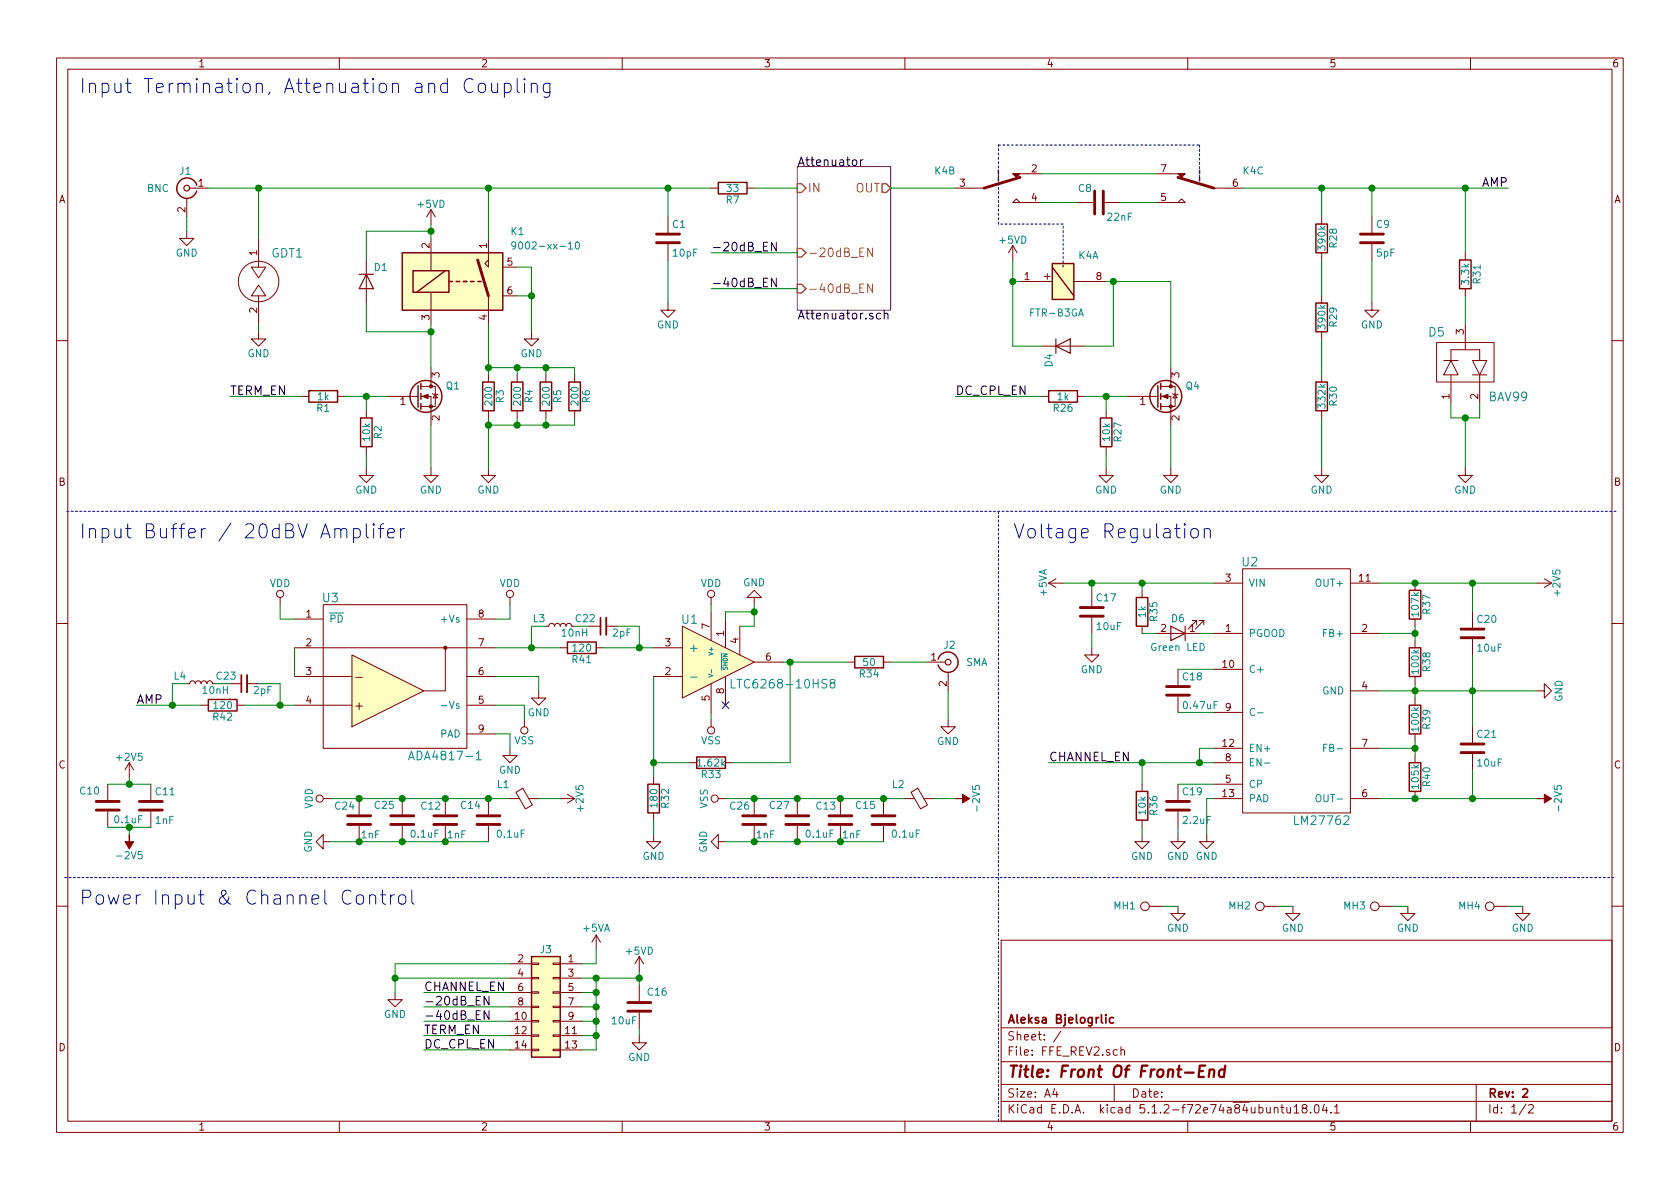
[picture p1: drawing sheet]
<svg xmlns="http://www.w3.org/2000/svg" width="297mm" height="210mm" viewBox="0 0 297 210" stroke-linecap="round" stroke-linejoin="round" font-family="sans-serif">
<defs><g id="words">
<g font-size="3.5" fill="#0000c2">
<text x="14" y="16.5">Input Termination, Attenuation and Coupling</text>
<text x="14" y="95.2">Input Buffer / 20dBV Amplifer</text>
<text x="179.1" y="95.2">Voltage Regulation</text>
<text x="14" y="160">Power Input &amp; Channel Control</text>
</g>
<text font-size="2.8" fill="#840000" x="178" y="190.5">Title: Front Of Front-End</text>
<g font-size="2.1">
<text x="141" y="29.4">Attenuator</text>
<text x="262" y="33">AMP</text>
<text x="125.7" y="44.4">-20dB_EN</text>
<text x="125.7" y="50.8">-40dB_EN</text>
<text x="141" y="56.5">Attenuator.sch</text>
<text x="40.6" y="69.8">TERM_EN</text>
<text x="168.9" y="69.8">DC_CPL_EN</text>
<text x="24.1" y="124.5">AMP</text>
<text x="185.4" y="134.6">CHANNEL_EN</text>
<text x="74.9" y="175.3">CHANNEL_EN</text>
<text x="74.9" y="177.8">-20dB_EN</text>
<text x="74.9" y="182.9">TERM_EN</text>
<text x="74.9" y="180.3">-40dB_EN</text>
<text x="74.9" y="185.4">DC_CPL_EN</text>
</g>
<g font-size="2.1" fill="#848400">
<text x="142.7" y="34">IN</text>
<text x="151.2" y="34">OUT</text>
<text x="142.7" y="45.5">-20dB_EN</text>
<text x="142.7" y="51.8">-40dB_EN</text>
</g>
<g font-size="2.1" fill="#008484">
<text x="48" y="45.5">GDT1</text>
<text x="252.7" y="59.5">D5</text>
<text x="263.3" y="70.9">BAV99</text>
<text x="219.6" y="100.1">U2</text>
<text x="57.1" y="106.5">U3</text>
<text x="120.6" y="110.3">U1</text>
<text x="121.7" y="115.3">+</text>
<text x="130.4" y="121.7">LTC6268-10HS8</text>
<text x="73.2" y="134.4">ADA4817-1</text>
<text x="229.2" y="145.9">LM27762</text>
</g>
<g font-size="2.1" fill="#840000">
<text x="62.9" y="125.5">+</text>
<text x="63.1" y="120.4">-</text>
<text x="178" y="184">Sheet: /</text>
<text x="178" y="181">Aleksa Bjelogrlic</text>
<text x="178" y="186.7">File: FFE_REV2.sch</text>
<text x="178" y="196.9">KiCad E.D.A. kicad 5.1.2-f72e74a84ubuntu18.04.1</text>
<text x="178" y="194.1">Size: A4</text>
<text x="200" y="194.1">Date:</text>
<text x="263" y="194.1">Rev: 2</text>
<text x="263" y="196.9">Id: 1/2</text>
</g>
<g font-size="1.8" fill="#840000">
<text x="35" y="11.9">1</text>
<text x="85" y="11.9">2</text>
<text x="135" y="11.9">3</text>
<text x="185" y="11.9">4</text>
<text x="235" y="11.9">5</text>
<text x="285" y="11.9">6</text>
<text x="10.4" y="35.9">A</text>
<text x="35.1" y="33">1</text>
<text x="169.7" y="33">3</text>
<text x="182.4" y="30.5">2</text>
<text x="182.4" y="35.6">4</text>
<text x="205.3" y="35.6">5</text>
<text x="205.3" y="30.5">7</text>
<text x="218" y="33">6</text>
<text x="285.4" y="35.9">A</text>
<text x="32.8" y="37.6" transform="rotate(-90 32.8 37.6)">2</text>
<text x="45.5" y="45.2" transform="rotate(-90 45.5 45.2)">1</text>
<text x="75.9" y="43.9" transform="rotate(-90 75.9 43.9)">2</text>
<text x="86.1" y="43.9" transform="rotate(-90 86.1 43.9)">1</text>
<text x="89.7" y="47">5</text>
<text x="89.7" y="52.1">6</text>
<text x="181.1" y="49.5">1</text>
<text x="193.8" y="49.5">8</text>
<text x="45.5" y="55.3" transform="rotate(-90 45.5 55.3)">2</text>
<text x="75.9" y="56.6" transform="rotate(-90 75.9 56.6)">3</text>
<text x="86.1" y="56.6" transform="rotate(-90 86.1 56.6)">4</text>
<text x="258.8" y="59.2" transform="rotate(-90 258.8 59.2)">3</text>
<text x="70.8" y="71.6">1</text>
<text x="77.7" y="66.8" transform="rotate(-90 77.7 66.8)">3</text>
<text x="201.6" y="71.6">1</text>
<text x="208.5" y="66.8" transform="rotate(-90 208.5 66.8)">3</text>
<text x="256.3" y="70.6" transform="rotate(-90 256.3 70.6)">1</text>
<text x="261.4" y="70.6" transform="rotate(-90 261.4 70.6)">2</text>
<text x="77.7" y="74.4" transform="rotate(-90 77.7 74.4)">2</text>
<text x="208.5" y="74.4" transform="rotate(-90 208.5 74.4)">2</text>
<text x="10.4" y="85.9">B</text>
<text x="285.4" y="85.9">B</text>
<text x="216.7" y="102.9">3</text>
<text x="240.3" y="102.9">11</text>
<text x="54.1" y="109.2">1</text>
<text x="84.6" y="109.2">8</text>
<text x="125.5" y="111.2" transform="rotate(-90 125.5 111.2)">7</text>
<text x="128" y="112.5" transform="rotate(-90 128 112.5)">1</text>
<text x="130.6" y="113.8" transform="rotate(-90 130.6 113.8)">4</text>
<text x="205.3" y="111.8">2</text>
<text x="210.3" y="111.8">1</text>
<text x="216.7" y="111.8">1</text>
<text x="240.8" y="111.8">2</text>
<text x="54.1" y="114.3">2</text>
<text x="54.1" y="119.4">3</text>
<text x="84.6" y="119.4">6</text>
<text x="84.6" y="114.3">7</text>
<text x="117.6" y="119.4">2</text>
<text x="117.6" y="114.3">3</text>
<text x="135.4" y="116.8">6</text>
<text x="164.6" y="116.8">1</text>
<text x="216.2" y="118.1">10</text>
<text x="54.1" y="124.5">4</text>
<text x="84.6" y="124.5">5</text>
<text x="125.5" y="123.9" transform="rotate(-90 125.5 123.9)">5</text>
<text x="128" y="122.7" transform="rotate(-90 128 122.7)">8</text>
<text x="167.4" y="121.4" transform="rotate(-90 167.4 121.4)">2</text>
<text x="216.7" y="125.7">9</text>
<text x="240.8" y="121.9">4</text>
<text x="84.6" y="129.5">9</text>
<text x="10.4" y="135.9">C</text>
<text x="216.2" y="132.1">12</text>
<text x="216.7" y="134.6">8</text>
<text x="240.8" y="132.1">7</text>
<text x="285.4" y="135.9">C</text>
<text x="216.2" y="141">13</text>
<text x="216.7" y="138.4">5</text>
<text x="240.8" y="141">6</text>
<text x="91.6" y="170.2">2</text>
<text x="91.6" y="172.7">4</text>
<text x="100.5" y="170.2">1</text>
<text x="100.5" y="172.7">3</text>
<text x="91.6" y="175.3">6</text>
<text x="91.6" y="177.8">8</text>
<text x="100.5" y="175.3">5</text>
<text x="100.5" y="177.8">7</text>
<text x="10.4" y="185.9">D</text>
<text x="91.1" y="180.3">10</text>
<text x="91.1" y="182.9">12</text>
<text x="91.1" y="185.4">14</text>
<text x="100" y="182.9">11</text>
<text x="100" y="185.4">13</text>
<text x="100.5" y="180.3">9</text>
<text x="285.4" y="185.9">D</text>
<text x="35" y="199.9">1</text>
<text x="85" y="199.9">2</text>
<text x="135" y="199.9">3</text>
<text x="185" y="199.9">4</text>
<text x="235" y="199.9">5</text>
<text x="285" y="199.9">6</text>
</g>
<g font-size="1.8" fill="#008484">
<text x="26" y="34">BNC</text>
<text x="31.8" y="30.9">J1</text>
<text x="128.4" y="36">R7</text>
<text x="128.6" y="34">33</text>
<text x="165.3" y="30.9">K4B</text>
<text x="190.7" y="34">C8</text>
<text x="219.8" y="30.9">K4C</text>
<text x="74" y="36.7">+5VD</text>
<text x="90.4" y="41.6">K1</text>
<text x="118.9" y="40.3">C1</text>
<text x="195.9" y="39">22nF</text>
<text x="243.4" y="40.3">C9</text>
<text x="31.1" y="45.4">GND</text>
<text x="66.2" y="47.9">D1</text>
<text x="91.9" y="44.1">9002-xx-10</text>
<text x="119.1" y="45.4">10pF</text>
<text x="176.8" y="43.1">+5VD</text>
<text x="190.7" y="45.8">K4A</text>
<text x="234.4" y="44.1" transform="rotate(-90 234.4 44.1)">390k</text>
<text x="236.4" y="43.8" transform="rotate(-90 236.4 43.8)">R28</text>
<text x="243.4" y="45.4">5pF</text>
<text x="259.8" y="50.2" transform="rotate(-90 259.8 50.2)">3.3k</text>
<text x="261.8" y="50.1" transform="rotate(-90 261.8 50.1)">R31</text>
<text x="116.2" y="58.1">GND</text>
<text x="182.3" y="56">FTR-B3GA</text>
<text x="234.4" y="58.1" transform="rotate(-90 234.4 58.1)">390k</text>
<text x="236.4" y="57.7" transform="rotate(-90 236.4 57.7)">R29</text>
<text x="240.6" y="58.1">GND</text>
<text x="43.8" y="63.2">GND</text>
<text x="92" y="63.2">GND</text>
<text x="186.1" y="64.9" transform="rotate(-90 186.1 64.9)">D4</text>
<text x="56.2" y="70.8">1k</text>
<text x="78.9" y="68.9">Q1</text>
<text x="87" y="71.5" transform="rotate(-90 87 71.5)">200</text>
<text x="89.1" y="71.2" transform="rotate(-90 89.1 71.2)">R3</text>
<text x="92.1" y="71.5" transform="rotate(-90 92.1 71.5)">200</text>
<text x="94.2" y="71.2" transform="rotate(-90 94.2 71.2)">R4</text>
<text x="97.2" y="71.5" transform="rotate(-90 97.2 71.5)">200</text>
<text x="99.2" y="71.2" transform="rotate(-90 99.2 71.2)">R5</text>
<text x="102.3" y="71.5" transform="rotate(-90 102.3 71.5)">200</text>
<text x="104.3" y="71.2" transform="rotate(-90 104.3 71.2)">R6</text>
<text x="187" y="70.8">1k</text>
<text x="209.7" y="68.9">Q4</text>
<text x="236.4" y="71.7" transform="rotate(-90 236.4 71.7)">R30</text>
<text x="56" y="72.8">R1</text>
<text x="65.5" y="77.9" transform="rotate(-90 65.5 77.9)">10k</text>
<text x="67.5" y="77.6" transform="rotate(-90 67.5 77.6)">R2</text>
<text x="186.3" y="72.8">R26</text>
<text x="196.3" y="77.9" transform="rotate(-90 196.3 77.9)">10k</text>
<text x="234.4" y="72" transform="rotate(-90 234.4 72)">332k</text>
<text x="198.3" y="78" transform="rotate(-90 198.3 78)">R27</text>
<text x="62.8" y="87.3">GND</text>
<text x="74.2" y="87.3">GND</text>
<text x="84.4" y="87.3">GND</text>
<text x="193.6" y="87.3">GND</text>
<text x="205.1" y="87.3">GND</text>
<text x="231.7" y="87.3">GND</text>
<text x="257.1" y="87.3">GND</text>
<text x="47.7" y="103.8">VDD</text>
<text x="88.3" y="103.8">VDD</text>
<text x="123.9" y="103.8">VDD</text>
<text x="131.4" y="103.7">GND</text>
<text x="185.1" y="105.3" transform="rotate(-90 185.1 105.3)">+5VA</text>
<text x="194" y="106.3">C17</text>
<text x="220.7" y="103.8">VIN</text>
<text x="233" y="103.8">OUT+</text>
<text x="275.9" y="105.2" transform="rotate(-90 275.9 105.2)">+2V5</text>
<text x="58.2" y="110.1">PD</text>
<text x="78.3" y="110.1">+Vs</text>
<text x="94.3" y="110">L3</text>
<text x="101.9" y="110">C22</text>
<text x="108.4" y="112.6">2pF</text>
<text x="194" y="111.4">10uF</text>
<text x="202.6" y="109.2" transform="rotate(-90 202.6 109.2)">1k</text>
<text x="204.6" y="109.8" transform="rotate(-90 204.6 109.8)">R35</text>
<text x="207.2" y="110">D6</text>
<text x="220.7" y="112.6">PGOOD</text>
<text x="234.4" y="112.6">FB+</text>
<text x="250.9" y="108.9" transform="rotate(-90 250.9 108.9)">107k</text>
<text x="252.9" y="108.5" transform="rotate(-90 252.9 108.5)">R37</text>
<text x="261.3" y="110.2">C20</text>
<text x="101.2" y="117.3">R41</text>
<text x="101.4" y="115.2">120</text>
<text x="152" y="119.8">R34</text>
<text x="152.7" y="117.8">50</text>
<text x="166.9" y="114.7">J2</text>
<text x="170.8" y="117.8">SMA</text>
<text x="191.1" y="119">GND</text>
<text x="203.7" y="115.1">Green LED</text>
<text x="220.7" y="119">C+</text>
<text x="250.9" y="119" transform="rotate(-90 250.9 119)">100k</text>
<text x="252.9" y="118.7" transform="rotate(-90 252.9 118.7)">R38</text>
<text x="261.3" y="115.2">10uF</text>
<text x="30.8" y="120.2">L4</text>
<text x="37.9" y="125.4">120</text>
<text x="38.4" y="120.2">C23</text>
<text x="44.9" y="122.7">2pF</text>
<text x="78.8" y="125.3">-Vs</text>
<text x="209.2" y="120.3">C18</text>
<text x="209.4" y="125.4">0.47uF</text>
<text x="233.8" y="122.8">GND</text>
<text x="276.3" y="124.1" transform="rotate(-90 276.3 124.1)">GND</text>
<text x="37.7" y="127.4">R42</text>
<text x="77.8" y="130.4">PAD</text>
<text x="91" y="131.6">VSS</text>
<text x="93.3" y="126.7">GND</text>
<text x="124" y="131.6">VSS</text>
<text x="165.7" y="131.7">GND</text>
<text x="250.9" y="129.2" transform="rotate(-90 250.9 129.2)">100k</text>
<text x="252.9" y="128.8" transform="rotate(-90 252.9 128.8)">R39</text>
<text x="261.3" y="130.5">C21</text>
<text x="20.8" y="134.5">+2V5</text>
<text x="88.2" y="136.8">GND</text>
<text x="123.5" y="135.6">1.62k</text>
<text x="124.1" y="137.6">R33</text>
<text x="220.7" y="133">EN+</text>
<text x="220.7" y="135.5">EN-</text>
<text x="234.8" y="133">FB-</text>
<text x="261.3" y="135.6">10uF</text>
<text x="14.2" y="140.5">C10</text>
<text x="27.6" y="140.6">C11</text>
<text x="55.3" y="143" transform="rotate(-90 55.3 143)">VDD</text>
<text x="59.3" y="143.2">C24</text>
<text x="66.3" y="143">C25</text>
<text x="74.5" y="143.2">C12</text>
<text x="81.6" y="143">C14</text>
<text x="88" y="139.4">L1</text>
<text x="103.2" y="143.3" transform="rotate(-90 103.2 143.3)">+2V5</text>
<text x="116.3" y="142.7" transform="rotate(-90 116.3 142.7)">180</text>
<text x="118.3" y="142.8" transform="rotate(-90 118.3 142.8)">R32</text>
<text x="125.1" y="143" transform="rotate(-90 125.1 143)">VSS</text>
<text x="129.2" y="143.2">C26</text>
<text x="136.2" y="143">C27</text>
<text x="144.4" y="143.2">C13</text>
<text x="151.4" y="143">C15</text>
<text x="157.8" y="139.4">L2</text>
<text x="173.3" y="143.1" transform="rotate(-90 173.3 143.1)">-2V5</text>
<text x="202.6" y="144" transform="rotate(-90 202.6 144)">10k</text>
<text x="209.2" y="140.6">C19</text>
<text x="220.7" y="141.9">PAD</text>
<text x="220.7" y="139.3">CP</text>
<text x="233.4" y="141.9">OUT-</text>
<text x="250.9" y="139.3" transform="rotate(-90 250.9 139.3)">105k</text>
<text x="252.9" y="139" transform="rotate(-90 252.9 139)">R40</text>
<text x="276.1" y="143.1" transform="rotate(-90 276.1 143.1)">-2V5</text>
<text x="20.4" y="145.6">0.1uF</text>
<text x="27.5" y="145.7">1nF</text>
<text x="63.9" y="148.3">1nF</text>
<text x="72.8" y="148.1">0.1uF</text>
<text x="79.2" y="148.3">1nF</text>
<text x="88" y="148.1">0.1uF</text>
<text x="133.8" y="148.3">1nF</text>
<text x="142.6" y="148.1">0.1uF</text>
<text x="149" y="148.3">1nF</text>
<text x="157.9" y="148.1">0.1uF</text>
<text x="204.6" y="144.1" transform="rotate(-90 204.6 144.1)">R36</text>
<text x="209.3" y="145.7">2.2uF</text>
<text x="21" y="151.9">-2V5</text>
<text x="55.2" y="150.8" transform="rotate(-90 55.2 150.8)">GND</text>
<text x="113.6" y="152.1">GND</text>
<text x="125" y="150.8" transform="rotate(-90 125 150.8)">GND</text>
<text x="200" y="152.1">GND</text>
<text x="206.3" y="152.1">GND GND</text>
<text x="197" y="160.8">MH1</text>
<text x="217.3" y="160.8">MH2</text>
<text x="237.6" y="160.8">MH3</text>
<text x="258" y="160.8">MH4</text>
<text x="103.2" y="164.8">+5VA</text>
<text x="206.3" y="164.8">GND</text>
<text x="226.6" y="164.8">GND</text>
<text x="247" y="164.8">GND</text>
<text x="267.3" y="164.8">GND</text>
<text x="95.6" y="168.6">J3</text>
<text x="110.8" y="168.8">+5VD</text>
<text x="114.6" y="176.1">C16</text>
<text x="67.9" y="180">GND</text>
<text x="108.3" y="181.1">10uF</text>
<text x="111.1" y="187.6">GND</text>
</g>
<g font-size="1.8" fill="#008400">
<text x="99.4" y="112.6">10nH</text>
<text x="35.9" y="122.7">10nH</text>
</g>
<g font-size="1.1" fill="#008484">
<text x="126.1" y="115.6" transform="rotate(-90 126.1 115.6)">V+</text>
<text x="128.7" y="118.6" transform="rotate(-90 128.7 118.6)">SHDN</text>
</g>
</g></defs>
<g fill="none" stroke="#840000" stroke-width=".18">
<path d="M10 10.3h277v189.9h-277zM12 12.2h273v186.1h-273zM60 10.3v1.9M110 10.3v1.9M160 10.3v1.9M210 10.3v1.9M260 10.3v1.9M33 35v3.3M33.5 33.3h3.3M76.2 37.1v2.5M76.2 37.1l-.8 1.2M76.2 37.1l.8 1.2"/>
<path d="M118.1 38.3v2.8M125.7 33.3h1.3M132.1 33.3h1.2M168.9 33.3h5.1M179.1 30.7h5M180.3 35.8l-.6-.6-.6 .6h5M190.5 35.8h2.8M195.3 35.8h2.8M204.5 35.8h5l-.6-.6-.6 .6M204.5 30.7h5M214.6 33.3h5.1M233.7 38.3v1.3"/>
<path d="M242.6 38.3v2.8M33 40.9v1.3h1.3l-1.3 1.2-1.3-1.2h1.3M44.4 47.2h2.6l-1.3 1.9zM45.7 50.4l1.3 1.9h-2.6zM45.7 58.7v1.2h1.3l-1.3 1.3-1.3-1.3h1.3M45.7 42.2v5M45.7 52.3v5.1M64.8 46v7.6M76.2 42.2v5.7M76.2 51.7v5.7M86.4 46v1.2l-.7-.6zM86.4 42.2v3.8"/>
<path d="M86.4 52.3v5.1M88.9 47.2h2.5M88.9 52.3h2.5M94 58.7v1.2h1.2l-1.2 1.3-1.3-1.3h1.3M118.1 53.6v1.3h1.3l-1.3 1.2-1.3-1.2h1.3M118.1 43.2v2.8M179.1 43.4l-.8 1.3M179.1 43.4v2.6M179.1 43.4l.7 1.3M180.3 49.8h5.8M184.7 48.9h1M185.2 48.4v1"/>
<path d="M189.9 49.8h5.7M233.7 44.7v1.3M233.7 52.3v1.3M233.7 58.7v1.2M242.6 53.6v1.3h1.2l-1.2 1.2-1.3-1.2h1.3M242.6 43.2v2.8M259.1 44.7v1.3M259.1 51v1.3M259.1 57.4v4.4M10 60.2h2M53.3 70.1h1.3M59.7 70.1h1.3"/>
<path d="M64.8 72.6v1.3M64.8 79v1.3M68.6 70.1h5.3M74.4 70.1h1.8v5.1M74.4 68.3h1.8M76.2 68.3h.8v3.6h-2.6M76.2 65v3.3M76.5 69.6l.1 .1h.7l.2 .1M77 69.7l.3 .7h-.7zM86.4 66.3v1.3M86.4 72.6v1.3M91.4 66.3v1.3"/>
<path d="M91.4 72.6v1.3M96.5 66.3v1.3M96.5 72.6v1.3M101.6 66.3v1.3M101.6 72.6v1.3M184.1 70.1h1.3M184.1 61.2h7.7M190.5 70.1h1.3M195.6 72.6v1.3M195.6 79v1.3M199.4 70.1h5.3M205.2 70.1h1.8v5.1"/>
<path d="M205.2 68.3h1.8M207 68.3h.8v3.6h-2.6M207 65v3.3M207.3 69.6l.1 .1h.8l.1 .1M207.8 69.7l.4 .7h-.8zM233.7 66.3v1.3M233.7 72.6v1.3M254 60.6h10.2v7h-10.2zM255.3 63.7h2.5M256.5 61.8v1.9zM256.5 61.8h5.1zM256.5 63.7l1.3 2.6h-2.5z"/>
<path d="M256.5 66.3v5.1M260.3 63.7h2.6l-1.3 2.6zM260.3 66.3h2.6M261.6 61.8v1.9zM261.6 66.3v5.1M285 60.2h2M64.8 82.8v1.3h1.2l-1.2 1.2-1.3-1.2h1.3M76.2 82.8v1.3h1.3l-1.3 1.2-1.3-1.2h1.3M86.4 82.8v1.3h1.2l-1.2 1.2-1.3-1.2h1.3M195.6 82.8v1.3h1.2l-1.2 1.2-1.3-1.2h1.3M207 82.8v1.3h1.3l-1.3 1.2-1.3-1.2h1.3M233.7 82.8v1.3h1.2l-1.2 1.2-1.3-1.2h1.3"/>
<path d="M259.1 82.8v1.3h1.2l-1.2 1.2-1.3-1.2h1.3M10 110.3h2M49.5 105.7v1.2M52.1 119.6h10.1M52.1 114.5h35.5M52.1 109.5h5M57.1 106.9h25.4v25.4h-25.4zM62.2 115.8l12.7 6.4-12.7 6.3zM78.7 114.5v7.7h-3.8M82.5 119.6h5.1M82.5 109.5h5.1M90.2 105.7v1.2"/>
<path d="M96.5 110.7h.5l.2-.3 .2-.2 .5 .2 .1 .3 .2-.3 .3-.2 .4 .2 .2 .3 .1-.3 .3-.2 .4 .2 .2 .3 .2-.4 .4-.1 .3 .2 .1 .3M99.1 114.5h1.2M104.1 110.7h2.1M105.4 114.5h1.3M107.2 110.7h2M115.6 119.6h5M115.6 114.5h5M120.6 110.7l12.7 6.4-12.7 6.3zM125.7 105.7v1.2M125.7 108.2v5.1M128.3 109.5v5M128.3 119.6v5.1"/>
<path d="M130.8 110.7v5.1M133.3 105.7h1.3l-1.3-1.3-1.2 1.3h1.2v1.2M133.3 117.1h5.1M149.9 117.1h1.2M156.2 117.1h1.3M163.8 117.1h3.3M167.6 118.9v3.3M185.4 103.1h2.6M185.4 103.1l1.3 .8M186.7 102.4l-1.3 .7M193 114.5v1.3h1.3l-1.3 1.3-1.2-1.3h1.2M193 104.4v2.8"/>
<path d="M193 109.2v2.8M201.9 104.4v1.3M201.9 110.7v1.3M204.5 112h7.6M208.3 118.4v2.8M211.6 110.5v-.8h-.8h.8l-1.5 1.5M212.9 110.5v-.8h-.8h.8l-1.6 1.5M214.6 112h5.1M214.6 118.4h5.1M214.6 103.1h5.1M219.7 100.6h19.1v43.2h-19.1zM238.8 112h5"/>
<path d="M238.8 103.1h5M250.2 103.1v1.3M250.2 109.5v1.2M250.2 113.3v1.2M250.2 119.6v1.3M260.3 108.2v2.8M260.3 113v2.8M271.8 103.1h2.5M273 102.4l1.3 .7M274.3 103.1l-1.3 .8M285 110.3h2M19 138.7v2.8"/>
<path d="M22.9 134.9l-.8 1.2M22.9 134.9v2.5M22.9 134.9l.7 1.2M26.7 138.7v2.8M33 120.9h.5l.2-.3 .2-.2 .5 .1 .1 .4 .2-.3 .3-.2 .4 .1 .2 .4 .1-.3 .3-.2 .4 .1 .2 .4 .2-.4 .4-.1 .3 .2 .1 .3M35.6 124.7h1.2M40.6 120.9h2.1M41.9 124.7h1.3M43.7 120.9h2M52.1 124.7h10.1M82.5 124.7h5.1M82.5 129.8h5.1"/>
<path d="M90.2 132.3v1.3h1.2l-1.2 1.3-1.3-1.3h1.3M92.7 127.2v1.3M95.2 122.2v1.2h1.3l-1.3 1.3-1.2-1.3h1.2M115.6 137.4v1.3M121.9 134.9h1.3M125.7 120.9v5.1M125.7 127.2v1.3M128.3 134.9h1.2M167.6 127.2v1.3h1.3l-1.3 1.3-1.2-1.3h1.2M201.9 138.7v1.2M208.3 123.2v2.8M208.3 138.7v2.8"/>
<path d="M214.6 134.9h5.1M214.6 132.3h5.1M214.6 138.7h5.1M214.6 126h5.1M238.8 132.3h5M238.8 122.2h5M250.2 123.4v1.3M250.2 129.8v1.3M250.2 133.6v1.3M250.2 139.9v1.3M260.3 128.5v2.8M260.3 133.3v2.8"/>
<path d="M271.8 122.2h1.2v-1.3l1.3 1.3-1.3 1.2v-1.2M19 143.5v2.8M26.7 143.5v2.8M57.1 148.8v1.3l-1.2-1.3 1.2-1.2v1.2h1.3M57.1 141.2h1.3M63.5 141.2v2.8M63.5 146v2.8M71.1 141.2v2.8M71.1 146v2.8M78.7 141.2v2.8M78.7 146v2.8M86.4 141.2v2.8"/>
<path d="M86.4 146v2.8M90.2 141.2h1.6M91.2 140.1l1.2-.7 1.7 2.9-1.2 .7zM93.5 141.2h1.7M99.1 141.2h2.5M100.3 140.5l1.3 .7M101.6 141.2l-1.3 .8M115.6 147.6v1.2h1.2l-1.2 1.3-1.3-1.3h1.3M115.6 143.8v1.2M127 148.8v1.3l-1.3-1.3 1.3-1.2v1.2h1.3M127 141.2h1.3M133.3 141.2v2.8"/>
<path d="M133.3 146v2.8M141 141.2v2.8M141 146v2.8M148.6 141.2v2.8M148.6 146v2.8M156.2 141.2v2.8M156.2 146v2.8M160 141.2h1.7M161.1 140.1l1.2-.7 1.7 2.9-1.2 .7zM163.3 141.2h1.8M201.9 147.6v1.2h1.3l-1.3 1.3-1.2-1.3h1.2M201.9 145v1.3"/>
<path d="M208.3 147.6v1.2h1.2l-1.2 1.3-1.3-1.3h1.3M208.3 143.5v2.8M213.4 147.6v1.2h1.2l-1.2 1.3-1.3-1.3h1.3M214.6 141.2h5.1M238.8 141.2h5M10 160.2h2M69.8 175.5v1.3h1.3l-1.3 1.2-1.2-1.2h1.2M90.2 170.4h3.8M90.2 173h3.8M90.2 175.5h3.8M90.2 178h3.8M94 177.9h1.2v.3h-1.2z"/>
<path d="M94 175.4h1.2v.2h-1.2zM94 172.8h1.2v.3h-1.2zM94 170.3h1.2v.3h-1.2zM97.8 177.9h1.3v.3h-1.3zM97.8 175.4h1.3v.2h-1.3zM97.8 172.8h1.3v.3h-1.3zM97.8 170.3h1.3v.3h-1.3zM99.1 170.4h3.8M99.1 173h3.8M99.1 175.5h3.8M99.1 178h3.8M105.4 165.3l-.8 1.3"/>
<path d="M105.4 165.3v2.6M105.4 165.3l.8 1.3M113 169.2v2.5M113 174.2v2.8M113 179.1v2.8M113 169.2l-.7 1.2M113 169.2l.8 1.2M177 166.3h108v32h-108zM203.2 160.3h2.5M208.3 160.3v1.2h1.2l-1.2 1.3-1.3-1.3h1.3M223.5 160.3h2.6M228.6 160.3v1.2h1.3l-1.3 1.3-1.3-1.3h1.3"/>
<path d="M243.8 160.3h2.6M248.9 160.3v1.2h1.3l-1.3 1.3-1.3-1.3h1.3M264.2 160.3h2.5M269.2 160.3v1.2h1.3l-1.3 1.3-1.2-1.3h1.2M285 160.2h2M60 198.3v1.9M90.2 180.6h3.8M90.2 183.1h3.8M90.2 185.7h3.8M94 185.5h1.2v.3h-1.2zM94 183h1.2v.3h-1.2zM94 180.5h1.2v.2h-1.2z"/>
<path d="M97.8 185.5h1.3v.3h-1.3zM97.8 183h1.3v.3h-1.3zM97.8 180.5h1.3v.2h-1.3zM99.1 180.6h3.8M99.1 183.1h3.8M99.1 185.7h3.8M110 198.3v1.9M113 183.1v1.3h-1.2l1.2 1.3 1.3-1.3h-1.3M160 198.3v1.9M177 194.8h108M177 191.8h108M177 187.8h108"/>
<path d="M177 181.8h108M186.5 192.5l-.4 1h1M186.8 193v1M187.6 182.3l-1.3 2M197 191.8v3M197.6 185.7l-.5-.1-.3 .3 .1 .6 .2 .1 .5-.1M198.2 185.7l.2-.1 .4 .1v.9M198.2 185.1v1.5M210 198.3v1.9M225.3 196l.1-.1a.37 .37 0 0 1 .6 .1v.8M226.4 195.8h.6M226.7 195.3v1.3l.3 .2"/>
<path d="M227.5 195.8l.1 .9 .3 .1 .3-.1M228.2 195.8v1M228.8 195.8l.4-.5v1.5M228.8 196.8h.9M230.5 196l-.2-.2-.1-.2 .3-.3h.3l.3 .3-.1 .2-.6 .2a.48 .48 0 0 0-.1 .7l.2 .1 .5-.1a.48 .48 0 0 0-.2-.7M231.7 196.7v.1M232.5 195.5l.4-.2a.94 .94 0 0 1 0 1.5l-.5-.3v-.6zM234.2 195.2l-.4 1.1h.9M234.5 195.8v1M235.3 196.7v.1M235.9 195.8l.5-.5v1.5M235.9 196.8h.9"/>
<path d="M260 198.3v1.9M261 191.8v6.5M269.8 195.2l-1.2 2M270.3 195.5l.2-.2h.3l.3 .5-.9 1h.9"/>
<circle cx="45.7" cy="49.8" r="3.6"/>
<circle cx="49.5" cy="105" r=".63"/>
<circle cx="78.7" cy="114.5" r=".18"/>
<circle cx="78.7" cy="114.5" r=".13"/>
<circle cx="78.7" cy="114.5" r=".28"/>
<circle cx="90.2" cy="105" r=".63"/>
<circle cx="125.7" cy="105" r=".63"/>
<circle cx="92.7" cy="129.2" r=".63"/>
<circle cx="125.7" cy="129.2" r=".63"/>
<circle cx="56.5" cy="141.2" r=".63"/>
<circle cx="126.4" cy="141.2" r=".63"/>
<circle cx="202.4" cy="160.3" r=".76"/>
<circle cx="222.8" cy="160.3" r=".76"/>
<circle cx="243.1" cy="160.3" r=".76"/>
<circle cx="263.4" cy="160.3" r=".76"/>
</g>
<path d="M42.7 119.4v3M106.2 109.2v3.1M195.5 179.4v.2M195.5 179.9v1M196.9 180l-.4-.1-.3 .3v.6l.3 .1 .4-.1M269.2 192.7l.3-.2h.3l.3 .5-.9 1h.9" fill="none" stroke="#840000" stroke-width=".3"/>
<path d="M212 189.4h.7M213.1 188.4h-1l-.2 2h1M213.9 189.3a.5 .5 0 0 1 .8 .1l-.1 1M213.9 189.1l-.2 1.3M216.5 189.2a.68 .68 0 0 0-1 .3v.8l.3 .1 .6-.1M216.6 188.4l-.2 2" fill="none" stroke="#840000" stroke-width=".41"/>
<g fill="none" stroke="#840000" stroke-width=".25">
<path d="M34.8 32.8a1.8 1.8 0 0 0-2.7-1.1 1.8 1.8 0 0 0-.1 3 1.8 1.8 0 0 0 2.8-.9M127 32.3h5.1v2h-5.1zM176.5 30.1v.6M176.5 31.4v.6M212.1 30.1v.6M212.1 31.4v.6M232.7 39.6h2v5.1h-2zM71.1 44.7h17.8v10.2h-17.8zM73 47.9h6.4v3.8h-6.4zM78.7 47.9l-5 3.8M79.4 49.8h.6M80.6 49.8h.7"/>
<path d="M81.9 49.8h.6M83.2 49.8h.6M84.5 49.8h.6M186.1 46.6h3.8v6.4h-3.8zM186.1 47.2l3.8 5.1M232.7 53.6h2v5.1h-2zM258.1 46h2v5h-2zM54.6 69.1h5.1v2h-5.1zM63.8 73.9h2v5.1h-2zM73.9 68.2v3.8M74.4 67.8v1M74.4 69.6v1"/>
<path d="M74.4 71.4v1M85.3 67.6h2.1v5h-2.1zM90.4 67.6h2.1v5h-2.1zM95.5 67.6h2v5h-2zM100.6 67.6h2v5h-2zM185.4 69.1h5.1v2h-5.1zM194.6 73.9h2v5.1h-2zM204.7 68.2v3.8M205.2 67.8v1M205.2 69.6v1M205.2 71.4v1M232.7 67.6h2v5h-2z"/>
<path d="M100.3 113.5h5.1v2.1h-5.1zM151.1 116.1h5.1v2h-5.1zM165.9 116.6a1.8 1.8 0 0 1 1.9-1.3 1.8 1.8 0 0 1 1.6 1.8M169.4 117.1a1.8 1.8 0 0 1-1.5 1.8 1.8 1.8 0 0 1-2-1.3M200.9 105.7h2v5h-2zM249.2 114.5h2v5.1h-2zM249.2 104.4h2v5.1h-2zM36.8 123.7h5.1v2h-5.1zM114.6 138.7h2v5.1h-2zM123.2 133.9h5.1v2h-5.1zM200.9 139.9h2v5.1h-2zM249.2 124.7h2v5.1h-2z"/>
<path d="M249.2 134.9h2v5h-2zM94 169.2h5.1v17.7h-5.1z"/>
<circle cx="75.3" cy="70.1" r="2.82"/>
<circle cx="206.1" cy="70.1" r="2.82"/>
</g>
<g fill="none" stroke="#840000" stroke-width=".2">
<path d="M63.5 48.5h2.5M64.8 48.5l1.2 2.5h-2.5zM186.7 59.9v2.6M186.7 61.2l2.5-1.3v2.6zM207 110.7l2.5 1.3-2.5 1.3zM209.5 110.7v2.6"/>
<circle cx="33" cy="33.3" r=".51"/>
<circle cx="167.6" cy="117.1" r=".51"/>
</g>
<g fill="#840000" stroke="#840000" stroke-width=".18">
<path d="M74.7 70.1l1-.4v.8z"/>
<path d="M205.5 70.1l1-.4v.8z"/>
<path d="M179.1 30.7h1.2l-.6 .7z"/>
<path d="M208.3 30.7h1.2l-.6 .7z"/>
<path d="M22.9 147.6v1.2h.7l-.7 1.3-.8-1.3h.8z"/>
<path d="M168.9 141.2h1.3v-.7l1.2 .7-1.2 .8v-.8z"/>
<path d="M271.8 141.2h1.2v-.7l1.3 .7-1.3 .8v-.8z"/>
<circle cx="76.2" cy="71.9" r=".28"/>
<circle cx="76.2" cy="68.3" r=".28"/>
<circle cx="207" cy="71.9" r=".28"/>
<circle cx="207" cy="68.3" r=".28"/>
</g>
<g fill="none" stroke="#840000" stroke-width=".51">
<path d="M180.3 31.4l-6.3 1.9M193.5 33.8v4M195.1 33.8v4M208.3 31.4l6.3 1.9M84.5 46l1.9 6.3M116.1 42.9h4M116.1 41.4h4M240.5 42.9h4.1M240.5 41.4h4.1M191 109h4.1M191 107.4h4.1M258.3 112.8h4.1"/>
<path d="M258.3 111.2h4.1M206.2 122.9h4.1M206.2 121.4h4.1M258.3 133.1h4.1M258.3 131.6h4.1M17 141.7h4.1M17 143.3h4.1M24.6 141.7h4.1M24.6 143.3h4.1M61.5 144.3h4M61.5 145.8h4M69.1 144.3h4.1"/>
<path d="M69.1 145.8h4.1M76.7 144.3h4.1M76.7 145.8h4.1M84.3 144.3h4.1M84.3 145.8h4.1M131.3 144.3h4.1M131.3 145.8h4.1M138.9 144.3h4.1M138.9 145.8h4.1M146.6 144.3h4M146.6 145.8h4M154.2 144.3h4"/>
<path d="M154.2 145.8h4M206.2 141.7h4.1M206.2 143.3h4.1M111 177.3h4.1M111 178.8h4.1"/>
</g>
<path d="M127.7 124.1l1.2 1.2M128.9 124.1l-1.2 1.2" fill="none" stroke="#000084" stroke-width=".18"/>
<g fill="none" stroke="#0000c2" stroke-width=".18">
<path d="M83.6 14.1a.94 .94 0 0 0-1-.1 .94 .94 0 0 0-.5 1 1.04 1.04 0 0 0 .2 1.1 1.04 1.04 0 0 0 1.2 .2l.1-.2M84.8 14.8a.69 .69 0 0 1 1.1 .4v.7a.67 .67 0 0 1-.7 .5 .67 .67 0 0 1-.6-.5v-.7zM86.9 14.7v1.3l.1 .3a.67 .67 0 0 0 1-.2M88 14.7v1.7M89.2 14.8a.82 .82 0 0 1 1 .2l.2 .2v.7l-.2 .2-.3 .3-.7-.1M89.2 14.7v2.5M91.4 13.9v2.1l.1 .3 .3 .1M92.7 13.9l-.1 .1 .1 .1 .2-.1-.2-.1v.2M92.7 14.7v1.7M93.9 15a.62 .62 0 0 1 1.1 .1v1.3M93.9 14.7v1.7M97.2 14.7v2a.67 .67 0 0 1-1 .4"/>
<path d="M97.2 14.8a.82 .82 0 0 0-1 .2l-.1 .2 .1 .9 .3 .3 .7-.1M59.2 93.7a.62 .62 0 0 1 1.1 .1v1.3M60.3 93.8l.1-.2a.61 .61 0 0 1 .9 .2v1.3M62.5 93.6a.79 .79 0 0 1 1.2 .3v.7l-.1 .3a.79 .79 0 0 1-1.1 .1M62.5 93.5v2.5M64.8 92.6v2.2l.3 .3M66.1 92.6l-.1 .2 .1 .1 .1-.1-.1-.2v.3M66.1 93.5v1.6M66.9 93.5h.9M67.8 92.6l-.4 .2-.1 .2v2.1M68.6 94.3l1.1-.2-.1-.5-.7-.1-.2 .1-.1 .2v1l.1 .2 .2 .1 .7-.1M70.8 93.5v1.6"/>
<path d="M71.5 93.5a.59 .59 0 0 0-.7 .4M209.5 92.6l-.1 .2 .1 .1 .1-.1-.1-.2v.3M209.5 93.5v1.6M210.7 93.7a.69 .69 0 0 1 1.2 .2v.7a.68 .68 0 0 1-.7 .5 .68 .68 0 0 1-.7-.5v-.7zM212.9 93.7a.62 .62 0 0 1 1.1 .1v1.3M212.9 93.5v1.6M63.2 158.3a.69 .69 0 0 1 1.1 .4v.7a.67 .67 0 0 1-.7 .5 .67 .67 0 0 1-.6-.5v-.7zM65.4 158.5a.62 .62 0 0 1 1 .1v1.3M65.4 158.2v1.7M67.3 158.2h.9M67.6 157.4v2.1l.1 .3 .5 .1M69 158.2v1.7"/>
<path d="M69.7 158.2a.59 .59 0 0 0-.7 .5M70.7 158.3a.69 .69 0 0 1 1.1 .4v.7a.67 .67 0 0 1-.7 .5 .67 .67 0 0 1-.6-.5v-.7zM72.8 157.4v2.1l.4 .4"/>
</g>
<path d="M141 29.5h16.5v25.4h-16.5z" fill="none" stroke="#840084" stroke-width=".18"/>
<path d="M152.1 28.3v1M152.6 28.3h-.3l-.2 .2M137.3 42.8v1.6l-.9-1.6v1.6M137.3 49.2v1.5l-.9-1.5v1.5M155.7 55.5l-.4-.1-.3 .1v.8a.48 .48 0 0 0 .7 0M156.3 55.5l.3-.1 .3 .1 .1 .9M156.3 54.9v1.5M86.5 176.2v1.5l-.9-1.5v1.5M86.5 178.7v1.6l-.9-1.6v1.6" fill="none" stroke="#000" stroke-width=".18"/>
<path d="M141 32.5h.7l.8 .8-.8 .7h-.7zM156 32.5h.7l.8 .8-.8 .7h-.7zM141 43.9h.7l.8 .8-.8 .8h-.7zM141 50.3h.7l.8 .7-.8 .8h-.7z" fill="none" stroke="#848400" stroke-width=".25"/>
<path d="M154.3 43.9v1.5l-.9-1.5v1.5M154.3 50.2v1.5l-.9-1.5v1.5" fill="none" stroke="#848400" stroke-width=".18"/>
<g fill="#ffffc2" stroke="#ffffc2" stroke-width=".18">
<path d="M186.1 46.6h3.8v6.4h-3.8z"/>
<path d="M71.1 44.7h17.8v10.2h-17.8z"/>
<path d="M94 169.2h5.1v17.7h-5.1z"/>
<path d="M62.2 115.8l12.7 6.4-12.7 6.3z"/>
<path d="M120.6 110.7l12.7 6.4-12.7 6.3z"/>
</g>
<g fill="none" stroke="#008484" stroke-width=".18">
<path d="M91.2 43.3l-.2 .3h-.3l-.2-.3v-.4l.2-.1h.3l.2 .2a.97 .97 0 0 1-.2 1h-.4M101.8 42.9l.2-.1a.69 .69 0 0 1 .5 .6 .69 .69 0 0 1-.5 .6l-.2-.1-.1-.3zM122.1 119.7h1.1M125.3 119.2l.8 .3-.8 .2M125.8 118.4v.6M72.2 134.4l.5-1.6 .6 1.6M72.4 133.9h.7M78.1 124.8h.9M84.2 133.3l.4-.5v1.6M84.2 134.4h.9M129.3 120.1v1.6h.7M147.1 120.8l-.3-.3v-.2l.3-.2 .5 .2-.1 .4-.6 .1a.48 .48 0 0 0 0 .8 .48 .48 0 0 0 .7-.1v-.4l-.3-.3"/>
<path d="M221.8 125.4a.6 .6 0 0 0-.8 .4 .6 .6 0 0 0 .6 .7l.2-.1M222.4 126.1h.9M223.6 134.9h.9M234 132.2h.4M234.6 131.6h-.6v1.3M232.8 140.7l.2-.2a.47 .47 0 0 1 .6 .4l-.1 .7-.3 .2-.3-.1a1 1 0 0 1-.1-1z"/>
</g>
<g fill="none" stroke="#008400" stroke-width=".18">
<path d="M33 38.3v2.6M36.8 33.3h88.9M45.7 33.3v8.9M76.2 39.6v2.6M86.4 33.3v8.9M118.1 33.3v5M133.3 33.3h7.7M157.5 33.3h11.4M184.1 35.8h6.4M184.1 30.7h20.4M198.1 35.8h6.4M219.7 33.3h47"/>
<path d="M233.7 33.3v5M242.6 33.3v5M259.1 33.3v11.4M45.7 57.4v1.3M64.8 53.6v5.1h11.4M76.2 40.9h-11.4v5.1M76.2 57.4v7.6M86.4 57.4v8.9M91.4 47.2h2.6v11.5M91.4 52.3h2.6M118.1 46v7.6M125.7 44.7h15.3"/>
<path d="M125.7 51h15.3M179.1 46v15.2h5M179.1 49.8h1.2M195.6 49.8h11.4v15.2M196.8 49.8v11.4h-5M233.7 46v6.3M233.7 59.9v6.4M242.6 46v7.6M259.1 52.3v5.1M40.6 70.1h12.7M61 70.1h7.6M64.8 70.1v2.5"/>
<path d="M76.2 75.2v7.6M86.4 73.9v8.9M86.4 65h15.2v1.3M91.4 65v1.3M91.4 73.9v1.3M96.5 65v1.3M96.5 73.9v1.3M101.6 73.9v1.3h-15.2M168.9 70.1h15.2M191.8 70.1h7.6M195.6 70.1v2.5M207 75.2v7.6"/>
<path d="M233.7 73.9v8.9M256.5 71.4v2.5h5.1v-2.5M259.1 73.9v8.9M64.8 80.3v2.5M195.6 80.3v2.5M49.5 106.9v2.6h2.6M52.1 114.5v5.1M87.6 114.5h11.5M87.6 119.6h7.6v2.6M90.2 106.9v2.6h-2.6M96.5 110.7h-2.5v3.8M106.7 114.5h8.9"/>
<path d="M109.2 110.7h3.8v3.8M115.6 119.6v17.8M125.7 106.9v1.3M133.3 106.9v3.8h-2.5M133.3 108.2h-5v1.3M138.4 117.1h11.5M139.7 117.1v17.8h-10.2M157.5 117.1h6.3M188 103.1h26.6M193 103.1v1.3M193 112v2.5M201.9 112h2.6"/>
<path d="M201.9 103.1v1.3M208.3 118.4h6.3M212.1 112h2.5M243.8 103.1h28M243.8 112h6.4M250.2 110.7v2.6M260.3 103.1v5.1M260.3 115.8v12.7M19 138.7h7.7M22.9 137.4v1.3M24.1 124.7h11.5M33 120.9h-2.5v3.8"/>
<path d="M43.2 124.7h8.9M45.7 120.9h3.8v3.8M87.6 129.8h2.6v2.5M87.6 124.7h5.1v2.5M115.6 134.9h6.3M125.7 126v1.2M167.6 122.2v5M185.4 134.9h29.2M201.9 134.9v3.8M208.3 138.7h6.3M208.3 126h6.3M214.6 132.3h-2.5v2.6"/>
<path d="M243.8 132.3h6.4M243.8 122.2h28M250.2 120.9v2.5M250.2 131.1v2.5M260.3 136.1v5.1M19 146.3h7.7M22.9 146.3v1.3M58.4 148.8h28M58.4 141.2h31.8M95.2 141.2h3.9M115.6 145v2.6M128.3 148.8h27.9"/>
<path d="M128.3 141.2h31.7M165.1 141.2h3.8M201.9 146.3v1.3M208.3 146.3v1.3M214.6 141.2h-1.2v6.4M243.8 141.2h28M69.8 173h20.4M74.9 178h15.3M74.9 175.5h15.3M90.2 170.4h-20.4v5.1M102.9 178h2.5M102.9 175.5h2.5"/>
<path d="M102.9 173h10.1M105.4 173v12.7h-2.5M105.4 167.9v2.5h-2.5M113 171.7v2.5M205.7 160.3h2.6M226.1 160.3h2.5M246.4 160.3h2.5M266.7 160.3h2.5M74.9 183.1h15.3M74.9 180.6h15.3M74.9 185.7h15.3M102.9 183.1h2.5"/>
<path d="M102.9 180.6h2.5M113 181.9v1.2"/>
</g>
<path d="M176.5 25.6h35.6M176.5 39.6v-14M188 39.6h-11.5M212.1 25.6v6.4M188 47.2v-7.6M176.5 90.4v108M285.7 90.4h-274.3M11.4 155.2h274.3" fill="none" stroke="#0000c2" stroke-width=".18" stroke-dasharray=".4 .4"/>
<g fill="#008400" stroke="#008400" stroke-width=".25">
<circle cx="259.1" cy="33.3" r=".51"/>
<circle cx="259.1" cy="73.9" r=".51"/>
<circle cx="118.1" cy="33.3" r=".51"/>
<circle cx="64.8" cy="70.1" r=".51"/>
<circle cx="76.2" cy="58.7" r=".51"/>
<circle cx="76.2" cy="40.9" r=".51"/>
<circle cx="45.7" cy="33.3" r=".51"/>
<circle cx="115.6" cy="134.9" r=".51"/>
<circle cx="139.7" cy="117.1" r=".51"/>
<circle cx="195.6" cy="70.1" r=".51"/>
<circle cx="196.9" cy="49.8" r=".51"/>
<circle cx="179.1" cy="49.8" r=".51"/>
<circle cx="22.9" cy="138.7" r=".51"/>
<circle cx="22.9" cy="146.3" r=".51"/>
<circle cx="86.4" cy="141.2" r=".51"/>
<circle cx="78.7" cy="141.2" r=".51"/>
<circle cx="78.7" cy="148.8" r=".51"/>
<circle cx="212.1" cy="134.9" r=".51"/>
<circle cx="250.2" cy="112" r=".51"/>
<circle cx="250.2" cy="122.2" r=".51"/>
<circle cx="250.2" cy="132.3" r=".51"/>
<circle cx="201.9" cy="103.1" r=".51"/>
<circle cx="193" cy="103.1" r=".51"/>
<circle cx="250.2" cy="103.1" r=".51"/>
<circle cx="250.2" cy="141.2" r=".51"/>
<circle cx="260.3" cy="122.2" r=".51"/>
<circle cx="260.3" cy="141.2" r=".51"/>
<circle cx="260.3" cy="103.1" r=".51"/>
<circle cx="113" cy="173" r=".51"/>
<circle cx="201.9" cy="134.9" r=".51"/>
<circle cx="233.7" cy="33.3" r=".51"/>
<circle cx="242.6" cy="33.3" r=".51"/>
<circle cx="105.4" cy="173" r=".51"/>
<circle cx="105.4" cy="183.1" r=".51"/>
<circle cx="105.4" cy="180.6" r=".51"/>
<circle cx="105.4" cy="178" r=".51"/>
<circle cx="105.4" cy="175.5" r=".51"/>
<circle cx="86.4" cy="33.3" r=".51"/>
<circle cx="94" cy="52.3" r=".51"/>
<circle cx="86.4" cy="65" r=".51"/>
<circle cx="91.4" cy="65" r=".51"/>
<circle cx="96.5" cy="65" r=".51"/>
<circle cx="86.4" cy="75.2" r=".51"/>
<circle cx="91.4" cy="75.2" r=".51"/>
<circle cx="96.5" cy="75.2" r=".51"/>
<circle cx="69.9" cy="173" r=".51"/>
<circle cx="113" cy="114.5" r=".51"/>
<circle cx="94" cy="114.5" r=".51"/>
<circle cx="49.5" cy="124.7" r=".51"/>
<circle cx="30.5" cy="124.7" r=".51"/>
<circle cx="71.1" cy="141.2" r=".51"/>
<circle cx="63.5" cy="141.2" r=".51"/>
<circle cx="63.5" cy="148.8" r=".51"/>
<circle cx="71.1" cy="148.8" r=".51"/>
<circle cx="156.2" cy="141.2" r=".51"/>
<circle cx="148.6" cy="141.2" r=".51"/>
<circle cx="148.6" cy="148.8" r=".51"/>
<circle cx="141" cy="141.2" r=".51"/>
<circle cx="133.4" cy="141.2" r=".51"/>
<circle cx="133.4" cy="148.8" r=".51"/>
<circle cx="141" cy="148.8" r=".51"/>
<circle cx="133.4" cy="108.2" r=".51"/>
</g>
<path d="M43.7 119.4v3M107.2 109.2v3.1" fill="none" stroke="#840000" stroke-width=".33"/>
<use href="#words"/>
</svg>
